VERSION 5.7 ;
  NOWIREEXTENSIONATPIN ON ;
  DIVIDERCHAR "/" ;
  BUSBITCHARS "[]" ;
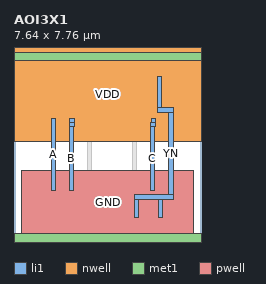
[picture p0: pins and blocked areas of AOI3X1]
MACRO AOI3X1
  CLASS CORE ;
  FOREIGN AOI3X1 ;
  ORIGIN 0.000 0.000 ;
  SIZE 7.640 BY 7.760 ;
  SYMMETRY X Y ;
  SITE unitrh ;
  PIN YN
    DIRECTION OUTPUT ;
    USE SIGNAL ;
    ANTENNADIFFAREA 0.963050 ;
    PORT
      LAYER li1 ;
        RECT 5.845 5.475 6.015 6.745 ;
        RECT 5.845 5.305 6.495 5.475 ;
        RECT 6.325 1.920 6.495 5.305 ;
        RECT 4.915 1.750 6.495 1.920 ;
        RECT 4.915 1.015 5.085 1.750 ;
        RECT 5.885 1.015 6.055 1.750 ;
    END
  END YN
  PIN A
    DIRECTION INPUT ;
    USE SIGNAL ;
    ANTENNAGATEAREA 1.033250 ;
    PORT
      LAYER li1 ;
        RECT 1.515 2.095 1.685 5.045 ;
    END
  END A
  PIN B
    DIRECTION INPUT ;
    USE SIGNAL ;
    ANTENNAGATEAREA 1.027250 ;
    PORT
      LAYER li1 ;
        RECT 2.285 4.890 2.455 5.045 ;
        RECT 2.255 4.715 2.455 4.890 ;
        RECT 2.255 2.095 2.425 4.715 ;
    END
  END B
  PIN C
    DIRECTION INPUT ;
    USE SIGNAL ;
    ANTENNAGATEAREA 1.026450 ;
    PORT
      LAYER li1 ;
        RECT 5.620 4.890 5.790 5.050 ;
        RECT 5.585 4.720 5.790 4.890 ;
        RECT 5.585 2.095 5.755 4.720 ;
    END
  END C
  PIN VDD
    DIRECTION INOUT ;
    USE POWER ;
    SHAPE ABUTMENT ;
    PORT
      LAYER nwell ;
        RECT 0.000 4.110 7.640 7.940 ;
      LAYER met1 ;
        RECT 0.000 7.410 7.640 7.760 ;
    END
  END VDD
  PIN GND
    DIRECTION INOUT ;
    USE GROUND ;
    SHAPE ABUTMENT ;
    PORT
      LAYER pwell ;
        RECT 0.320 0.350 7.320 2.900 ;
        RECT 0.000 0.000 7.640 0.350 ;
      LAYER met1 ;
        RECT 0.000 0.000 7.640 0.350 ;
    END
  END GND
  OBS
      LAYER li1 ;
        RECT 0.000 7.410 7.640 7.760 ;
        RECT 0.320 4.290 0.660 7.410 ;
        RECT 1.195 5.315 1.365 7.410 ;
        RECT 1.635 5.465 1.805 7.200 ;
        RECT 2.075 5.735 2.245 7.410 ;
        RECT 2.515 5.465 2.685 7.200 ;
        RECT 2.955 5.735 3.125 7.410 ;
        RECT 1.635 5.295 3.165 5.465 ;
        RECT 0.320 0.350 0.660 2.900 ;
        RECT 1.100 1.845 1.270 1.925 ;
        RECT 2.070 1.845 2.240 1.925 ;
        RECT 2.995 1.920 3.165 5.295 ;
        RECT 3.650 4.290 3.990 7.410 ;
        RECT 4.525 5.475 4.695 7.205 ;
        RECT 4.965 5.735 5.135 7.410 ;
        RECT 5.405 7.005 6.455 7.175 ;
        RECT 5.405 5.475 5.575 7.005 ;
        RECT 6.285 5.735 6.455 7.005 ;
        RECT 4.525 5.305 5.575 5.475 ;
        RECT 4.690 4.890 4.860 5.050 ;
        RECT 4.690 4.720 5.015 4.890 ;
        RECT 1.100 1.675 2.240 1.845 ;
        RECT 1.100 0.545 1.270 1.675 ;
        RECT 1.585 0.350 1.755 1.300 ;
        RECT 2.070 0.795 2.240 1.675 ;
        RECT 2.555 1.750 3.165 1.920 ;
        RECT 2.555 1.015 2.725 1.750 ;
        RECT 3.040 0.795 3.210 1.565 ;
        RECT 2.070 0.625 3.210 0.795 ;
        RECT 2.070 0.545 2.240 0.625 ;
        RECT 3.040 0.545 3.210 0.625 ;
        RECT 3.650 0.350 3.990 2.900 ;
        RECT 4.845 2.095 5.015 4.720 ;
        RECT 6.980 4.290 7.320 7.410 ;
        RECT 4.430 0.795 4.600 1.925 ;
        RECT 5.400 0.795 5.570 1.570 ;
        RECT 6.370 0.795 6.540 1.570 ;
        RECT 4.430 0.625 6.540 0.795 ;
        RECT 4.430 0.350 4.600 0.625 ;
        RECT 4.915 0.350 5.085 0.625 ;
        RECT 5.400 0.350 5.570 0.625 ;
        RECT 5.885 0.350 6.055 0.625 ;
        RECT 6.370 0.350 6.540 0.625 ;
        RECT 6.980 0.350 7.320 2.900 ;
        RECT 0.000 0.000 7.640 0.350 ;
      LAYER mcon ;
        RECT 0.775 7.495 0.945 7.665 ;
        RECT 1.145 7.495 1.315 7.665 ;
        RECT 1.515 7.495 1.685 7.665 ;
        RECT 1.885 7.495 2.055 7.665 ;
        RECT 2.255 7.495 2.425 7.665 ;
        RECT 2.625 7.495 2.795 7.665 ;
        RECT 2.995 7.495 3.165 7.665 ;
        RECT 3.365 7.495 3.535 7.665 ;
        RECT 4.105 7.495 4.275 7.665 ;
        RECT 4.475 7.495 4.645 7.665 ;
        RECT 4.845 7.495 5.015 7.665 ;
        RECT 5.215 7.495 5.385 7.665 ;
        RECT 5.585 7.495 5.755 7.665 ;
        RECT 5.955 7.495 6.125 7.665 ;
        RECT 6.325 7.495 6.495 7.665 ;
        RECT 6.695 7.495 6.865 7.665 ;
        RECT 2.995 2.685 3.165 2.855 ;
        RECT 4.845 2.685 5.015 2.855 ;
        RECT 0.775 0.095 0.945 0.265 ;
        RECT 1.145 0.095 1.315 0.265 ;
        RECT 1.515 0.095 1.685 0.265 ;
        RECT 1.885 0.095 2.055 0.265 ;
        RECT 2.255 0.095 2.425 0.265 ;
        RECT 2.625 0.095 2.795 0.265 ;
        RECT 2.995 0.095 3.165 0.265 ;
        RECT 3.365 0.095 3.535 0.265 ;
        RECT 4.105 0.095 4.275 0.265 ;
        RECT 4.475 0.095 4.645 0.265 ;
        RECT 4.845 0.095 5.015 0.265 ;
        RECT 5.215 0.095 5.385 0.265 ;
        RECT 5.585 0.095 5.755 0.265 ;
        RECT 5.955 0.095 6.125 0.265 ;
        RECT 6.325 0.095 6.495 0.265 ;
        RECT 6.695 0.095 6.865 0.265 ;
      LAYER met1 ;
        RECT 2.965 2.855 3.195 2.885 ;
        RECT 4.815 2.855 5.045 2.885 ;
        RECT 2.935 2.685 5.075 2.855 ;
        RECT 2.965 2.655 3.195 2.685 ;
        RECT 4.815 2.655 5.045 2.685 ;
  END
END AOI3X1
END LIBRARY

